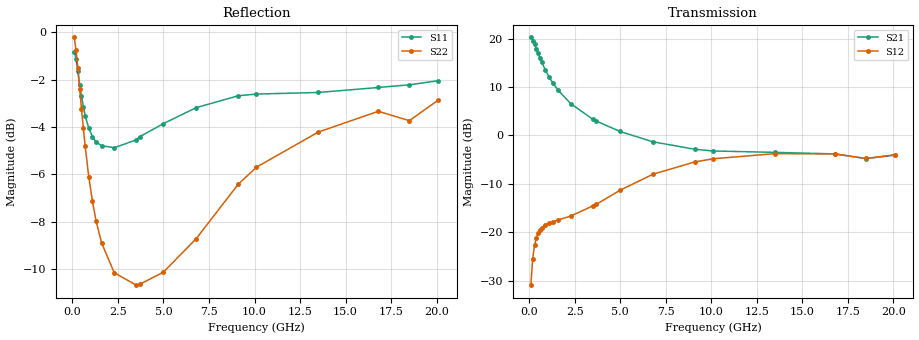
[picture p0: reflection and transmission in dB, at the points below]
!  Infineon Technologies AG
! BFR380L3 , PF131585-7, No.6, Th 09.10.01, soldered on pcb-board, measured with PP GSG850
!  Vce=3.5 V,  Ic=3.0 mA
! Common Emitter S-Parameters:  15. November 2001
#  GHz  S  MA  R  50
! f  S11  S21  S12  S22
! GHz  Mag  Ang  Mag  Ang  Mag  Ang  Mag  Ang
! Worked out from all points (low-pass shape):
!   201 points, 100 MHz to 20.1 GHz, reference 50 ohm
!   highest |S21| = 20.25 dB at 100 MHz (marker M1); lowest = -4.8 dB at 18.5 GHz (marker M2)
!   |S21| within 3 dB of the highest: start of sweep to 467.3 MHz
!   lowest |S11| = -4.9 dB at 2.3 GHz (marker M3), VSWR 3.65, Z = 13.7 + j0.725 ohm
!   |S11| at or under -10 dB: nowhere
!   |S22| runs from -10.7 to -0.2 dB; largest |S21 - S12| = 10
!   S11 on the Smith chart (normalised r, x): 100 MHz: 1.37, -5.14; 400 MHz: 0.35, -1.28; 1.1 GHz: 0.28, -0.37; 3.7 GHz: 0.27, +0.26; 9.1 GHz: 0.33, +1.05; 20.1 GHz: 0.97, +2.54
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0.1  0.9101 -20.6  10.3 165.7  0.02848 76.6  0.9748 -11.5
0.2  0.8784 -40.4  9.534 152.8  0.05346 68.4  0.9166 -22.0
0.3  0.8298 -58.1  8.715 141.4  0.07313 59.5  0.8389 -30.7
0.4  0.7731 -73.3  7.846 131.8  0.08758 52.7  0.7604 -37.6
0.5  0.7329 -86.8  7.033 123.8  0.09793 47.6  0.6892 -43.0
0.6  0.6962 -98.1  6.313 117.1  0.1059 43.9  0.6273 -47.3
0.7  0.6668 -108.1  5.708 111.2  0.1117 40.8  0.5753 -50.6
0.9  0.6268 -124.2  4.73 101.9  0.1195 37.0  0.4952 -55.6
1.1  0.6019 -137.0  4.031 94.4  0.125 35.1  0.4403 -59.3
1.3  0.5865 -147.4  3.498 88.0  0.1287 34.4  0.3997 -62.2
1.6  0.5759 -160.1  2.919 79.9  0.1341 34.7  0.3593 -66.1
2.3  0.5703 178.2  2.122 64.8  0.1474 38.4  0.3107 -75.4
3.5  0.5922 152.1  1.471 44.6  0.1873 46.5  0.2925 -94.9
3.7  0.6017 149.2  1.406 42.0  0.1949 47.2  0.2937 -99.4
5  0.6412 128.4  1.099 25.8  0.272 48.9  0.3116 -125.1
6.8  0.6929 105.7  0.8599 10.3  0.3977 40.8  0.3666 -163.1
9.1  0.7339 84.4  0.7206 -1.4  0.5329 23.9  0.4772 157.7
10.1  0.7402 76.8  0.6915 -5.2  0.5745 16.2  0.5186 142.9
13.5  0.7458 58.5  0.6689 -18.4  0.6489 -7.8  0.6153 105.2
16.8  0.7642 47.0  0.6448 -30.8  0.6456 -25.0  0.6807 80.1
18.5  0.7742 45.6  0.5764 -38.2  0.579 -33.7  0.6504 73.7
20.1  0.7898 38.5  0.627 -42.4  0.632 -39.0  0.7192 62.4
